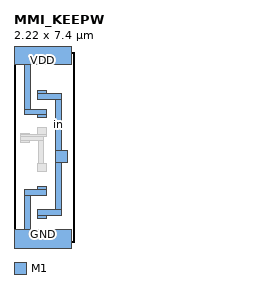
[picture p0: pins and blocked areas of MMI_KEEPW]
MACRO MMI_KEEPW
	CLASS CORE ;
	FOREIGN MMI_KEEPW 0 0 ;
	SIZE 2.22 BY 7.4 ;
	SYMMETRY X Y ;
	SITE CORE1 ;
	PIN GND
		DIRECTION inout ;
		USE GROUND ;
		PORT
			LAYER M1 ;
			RECT 0.93 2.06 1.27 2.17 ;
			LAYER M1 ;
			RECT 0.395 1.83 1.27 2.06 ;
			LAYER M1 ;
			RECT 0.395 0.5 0.625 1.83 ;
			LAYER M1 ;
			RECT 0 -0.5 2.22 0.5 ;
		END
	END GND
	PIN VDD
		DIRECTION inout ;
		USE POWER ;
		PORT
			LAYER M1 ;
			RECT 0 6.9 2.22 7.9 ;
			LAYER M1 ;
			RECT 0.425 5.18 0.655 6.9 ;
			LAYER M1 ;
			RECT 0.425 4.95 1.27 5.18 ;
			LAYER M1 ;
			RECT 0.93 4.84 1.27 4.95 ;
		END
	END VDD
	PIN in
		DIRECTION inout ;
		USE SIGNAL ;
		PORT
			LAYER M1 ;
			RECT 0.93 5.79 1.27 5.9 ;
			LAYER M1 ;
			RECT 0.93 5.56 1.855 5.79 ;
			LAYER M1 ;
			RECT 1.625 3.555 1.855 5.56 ;
			LAYER M1 ;
			RECT 1.625 3.105 2.075 3.555 ;
			LAYER M1 ;
			RECT 1.625 1.27 1.855 3.105 ;
			LAYER M1 ;
			RECT 0.93 1.04 1.855 1.27 ;
			LAYER M1 ;
			RECT 0.93 0.93 1.27 1.04 ;
		END
		AntennaGateArea 0.2268 ;
		AntennaDiffArea 0.4032 ;
	END in
	OBS
		LAYER M1 ;
		RECT 0.27 4.175 0.61 4.22 ;
		LAYER M1 ;
		RECT 0.93 4.175 1.27 4.46 ;
		LAYER M1 ;
		RECT 0.27 4.12 1.27 4.175 ;
		LAYER M1 ;
		RECT 0.27 3.945 1.165 4.12 ;
		LAYER M1 ;
		RECT 0.27 3.88 0.61 3.945 ;
		LAYER M1 ;
		RECT 0.935 3.07 1.165 3.945 ;
		LAYER M1 ;
		RECT 0.93 2.73 1.27 3.07 ;
	END
END MMI_KEEPW
